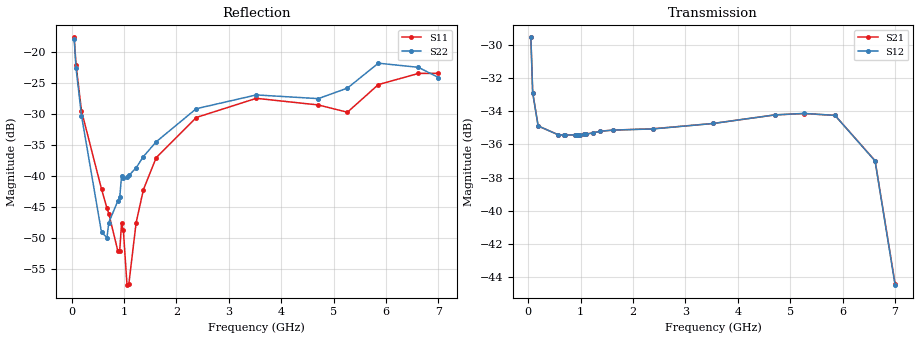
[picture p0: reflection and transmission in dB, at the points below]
! Integrated Device Technology
! Corporate Headquarters
! 6024 Silver Creek Valley Road
! San Jose, CA 95138  USA
! Phone:  1-408-284-8200
! Toll Free:  1-800-223-1366
! Webpage:  http://www.idt.com/
! Timing and RF Division
! 515 Groton Road, Suite 102
! Westford, MA 01886-6024
! Device:  F2258
! Description: Voltage Variable RF Attenuator
! Frequency:  50.0 -  6000.00 MHz
! Package:  3x3 mm Thin QFN Plastic Package: 16 pin
! Ports:  2 RF, 2 DC
!  Pin  1  = NC
!  Pin  2  = NC
!  Pin  3  = RF2  = Port 2
!  Pin  4  = GND
!  Pin  5  = Vdd
!  Pin  6  = NC
!  Pin  7  = VCTRL
!  Pin  8  = NC
!  Pin  9  = GND
!  Pin 10  = RF1  = Port 1
!  Pin 11  = NC
!  Pin 12  = NC
!  Pin 13  = NC
!  Pin 14  = NC
!  Pin 15  = NC
!  Pin 16  = NC
! Vcntrl:  2.270 Volts
! Vdd:  +3.300 Volts
! Current:  1.151 mA
! Data:  The device was measured on a the F2258 evaluation board which has
!  individual transmission lines to the RF pins.  Data was collected
!  using a calibrated network analyzer.  The evaluation board was
!  de-embedded using a TRL calibration technique.
!  The reference plane is the edge of the package pin.
! Misc:  SN 10
!  Action Tracker AT0285
! Date Measured:  2014-12-10
! Date:  2016-01-13  MJV
! Note:
!  Integrated Device Technology supplies this data as a sample of measured
!  data at the package pin for this product.  Your particular data for this
!  product may vary.
!  Data was taken at 25 degrees C.
!  Integrated Device Technology reserves the right to change this data at anytime.
!Freq_(GHz)  S11M_(dB)  S11P_(deg)  S21M_(dB)  S21P_(deg)  S12M_(dB)  S12P_(deg)  S22M_(dB)  S22P_(deg)
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# GHz S dB R 50
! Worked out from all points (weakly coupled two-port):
!   201 points, 50 MHz to 7 GHz, reference 50 ohm
!   highest |S21| = -29.52 dB at 50 MHz (marker M1); lowest = -44.4 dB at 7 GHz (marker M2)
!   lowest |S11| = -57.6 dB at 1.058 GHz (marker M3), VSWR 1.00, Z = 49.9 + j0.0559 ohm
!   |S11| at or under -10 dB: start of sweep to end of sweep
!   |S22| runs from -50.4 to -17.9 dB; largest |S21 - S12| = 8.5e-05
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0.05  -17.56 -111.0  -29.52 -68.4  -29.52 -68.4  -17.85 -111.3
0.08475  -21.98 -107.4  -32.87 -48.7  -32.87 -48.7  -22.53 -107.4
0.189  -29.43 -109.4  -34.88 -24.7  -34.88 -24.7  -30.19 -109.4
0.57125  -42.09 -124.7  -35.41 -10.4  -35.41 -10.4  -49.09 -162.3
0.6755  -45.18 -131.7  -35.43 -9.5  -35.43 -9.4  -49.91 143.3
0.71025  -46.04 -137.6  -35.43 -9.2  -35.43 -9.2  -47.48 133.3
0.884  -52.13 166.4  -35.42 -8.4  -35.42 -8.4  -43.96 115.9
0.91875  -52.05 150.0  -35.42 -8.3  -35.42 -8.3  -43.43 113.7
0.9535  -47.56 -162.6  -35.43 -8.2  -35.43 -8.2  -39.95 120.9
0.98825  -48.77 -174.0  -35.42 -8.1  -35.41 -8.1  -40.28 118.5
1.05775  -57.60 154.8  -35.39 -8.0  -35.39 -7.9  -40.15 103.9
1.0925  -57.43 120.4  -35.38 -7.9  -35.38 -7.9  -39.88 99.7
1.2315  -47.51 47.1  -35.30 -7.9  -35.30 -7.9  -38.64 78.5
1.3705  -42.17 36.9  -35.20 -8.4  -35.20 -8.3  -36.82 65.8
1.61375  -37.01 32.8  -35.13 -9.6  -35.13 -9.6  -34.44 52.7
2.37825  -30.51 48.2  -35.05 -13.2  -35.06 -13.2  -29.09 43.1
3.525  -27.41 91.7  -34.73 -19.6  -34.73 -19.6  -26.86 67.2
4.7065  -28.48 95.7  -34.21 -28.8  -34.21 -28.8  -27.46 58.4
5.2625  -29.66 54.4  -34.13 -34.9  -34.12 -34.9  -25.76 21.1
5.85325  -25.19 29.9  -34.24 -45.5  -34.24 -45.5  -21.73 -2.6
6.61775  -23.39 49.7  -36.98 -68.6  -37.00 -68.7  -22.40 -44.4
7  -23.37 84.5  -44.43 -61.7  -44.51 -61.1  -24.05 -129.9
